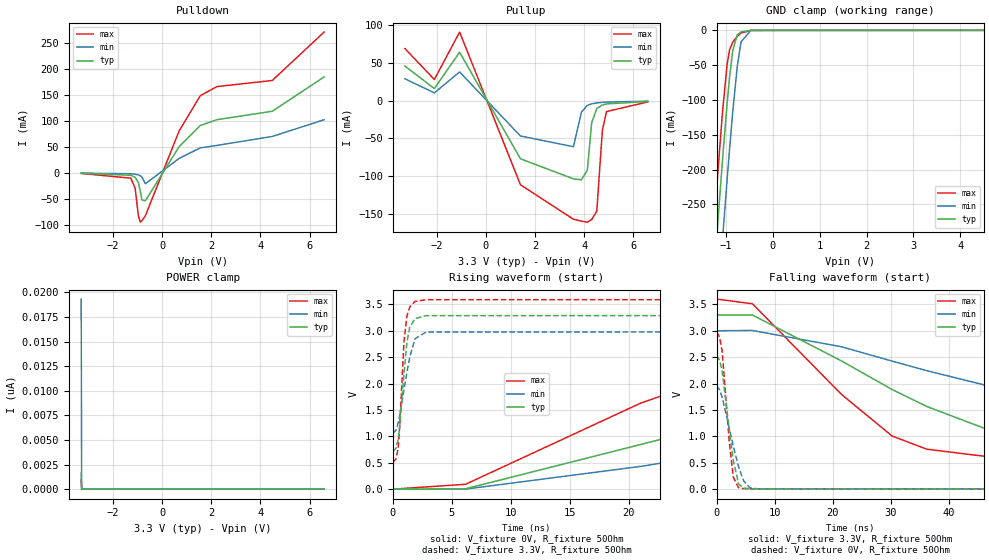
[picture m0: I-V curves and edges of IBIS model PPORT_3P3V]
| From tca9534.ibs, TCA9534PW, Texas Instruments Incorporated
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[Model]   PPORT_3P3V
Model_type   I/O
Polarity   Non-Inverting
Enable   Active-Low
Vinl = .8
Vinh = 2
Vmeas = 1.65
Vref = 3.3
Cref = 15pF
Rref = 50
|   typ   min   max
|   (nom PVT)   (slow PVT)   (fast PVT)
C_comp   2.468p   2.379p   2.720p
|C_comp (ON state)   2.695p   2.535p   2.941p
|C_comp (OFF state)   2.468p   2.379p   2.720p
| Where   nom PVT is  Nominal Process, 3.3V, 27C
|   Fast PVT is Strong Process, 3.6V, -40C
|   Slow PVT is Weak Process, 3.0V, 125C
[Voltage Range]   3.3   3   3.6
[Temperature Range]   27   125   -40
[Pullup Reference]   3.3   3   3.6
[Pulldown Reference]   -0   -0   -0
[Power Clamp Reference]   3.3   3   3.6
[GND Clamp Reference]   -0   -0   -0
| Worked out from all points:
|   slope of the pulldown table from 0 to 0.495 V, typ, clamps not added: 13.1 ohm
|   slope of the pullup table from 0 to 0.495 V, typ, clamps not added: 14.2 ohm
|   GND clamp passes 1 mA (typ) near -0.62 V on its own axis
|   falling waveform, V_fixture 3.3V, R_fixture 50Ohm: 20-80 % time 27.7ns typ, 49.7ns min, 17.6ns max; typ from 3.3 V to 0.708 V
|   rising waveform, V_fixture 0V, R_fixture 50Ohm: 20-80 % time 30.4ns typ, 44.4ns min, 19.6ns max; typ from 0 V to 2.53 V
|   rising waveform, V_fixture 3.3V, R_fixture 50Ohm: 20-80 % time 596ps typ, 918ps min, 448ps max; typ from 0.708 V to 3.3 V
|   falling waveform, V_fixture 0V, R_fixture 50Ohm: 20-80 % time 1.69ns typ, 2.5ns min, 1.29ns max; typ from 2.53 V to 0 V
[Pulldown]
|   Voltage   I(typ)   I(min)   I(max)
-3.3V     -639.1uA   -277.8uA   -1.004mA
-1.28V    -4.532mA   -1.594mA   -10.09mA
-1.102V   -8.451mA   -2.443mA   -29.46mA
-973.5mV  -18.23mA   -3.774mA   -81.98mA
-894.3mV  -35.11mA   -5.41mA    -95.02mA
-825mV    -52.14mA   -8.089mA   -92.21mA
-686.4mV  -53.71mA   -20.79mA   -82.53mA
689.7mV   50.71mA    28.1mA     81.12mA
1.551V    91.54mA    48.35mA    149.1mA
2.224V    102.7mA    53.06mA    166.5mA
4.481V    119mA      70.39mA    178.4mA
6.59V     185.1mA    102.6mA    271.7mA
[GND Clamp]
|   Voltage   I(typ)   I(min)   I(max)
-3.3V     -2.346A    -2.455A    -2.279A
-1.32V    -412.1mA   -528.2mA   -339.5mA
-1.261V   -356.7mA   -472.8mA   -284.2mA
-1.211V   -311mA     -426.9mA   -238.7mA
-1.073V   -186.8mA   -300.8mA   -117.9mA
-973.5mV  -104.8mA   -214mA     -48.36mA
-924mV    -68.57mA   -172.4mA   -28.41mA
-854.7mV  -29.13mA   -117.3mA   -17.02mA
-755.7mV  -6.263mA   -50.5mA    -8.57mA
-676.5mV  -2.232mA   -16.53mA   -3.84mA
-468.6mV  -59.06uA   -162.9uA   -73.71uA
6.59V     0A         0A         0A
[Pullup]
|   Voltage   I(typ)   I(min)   I(max)
-3.3V     45.75mA    28.86mA    68.89mA
-2.102V   15.93mA    10.19mA    27.88mA
-1.073V   64.02mA    37.93mA    90.75mA
1.403V    -77.2mA    -46.97mA   -111.6mA
3.561V    -103.7mA   -61.12mA   -157.3mA
3.887V    -105mA     -15.25mA   -159.8mA
4.125V    -92.21mA   -6.397mA   -161.2mA
4.303V    -29.45mA   -4.336mA   -157.7mA
4.511V    -10.5mA    -3.127mA   -146.5mA
4.739V    -5.875mA   -2.386mA   -39.33mA
4.907V    -4.4mA     -2.028mA   -14.57mA
6.59V     -1.226mA   -802.4uA   -1.786mA
[POWER Clamp]
|   Voltage   I(typ)   I(min)   I(max)
-3.3V     1.647nA    19.33nA    956.4pA
-3.28V    0A         0A         0A
-3.27V    0A         0A         0A
6.59V     0A         0A         0A
[Ramp]
R_load = 50
|   typ   min   max
dV/dt_r   1.51993/3.02056e-08   1.17587/4.4155e-08   1.78552/1.95401e-08
dV/dt_f   1.55534/2.77013e-08   1.1674/4.95217e-08   1.85505/1.75559e-08
[Falling Waveform]
V_fixture = 3.3V
V_fixture_min = 3V
V_fixture_max = 3.6V
R_fixture = 50Ohm
C_fixture = 0F
|   Time   V(typ)   V(min)   V(max)
0s        3.3V       3V         3.6V
6.173ns   3.298V     3.005V     3.511V
21.49ns   2.429V     2.697V     1.795V
30.21ns   1.887V     2.425V     1.006V
36.2ns    1.565V     2.243V     756.4mV
46.26ns   1.145V     1.969V     620.5mV
58.44ns   913.1mV    1.696V     565.3mV
80.73ns   785.3mV    1.362V     531.6mV
119ns     727mV      1.15V      512.5mV
399.9ns   707.8mV    1.054V     508.3mV
[Rising Waveform]
V_fixture = 0V
V_fixture_min = 0V
V_fixture_max = 0V
R_fixture = 50Ohm
C_fixture = 0F
|   Time   V(typ)   V(min)   V(max)
0s        1.304uV    1.505uV    1.202uV
6.173ns   6.889mV    1.278mV    92.64mV
21.01ns   845.3mV    430.8mV    1.628V
30.85ns   1.407V     777.4mV    2.394V
39.01ns   1.781V     1.033V     2.707V
49.88ns   2.131V     1.306V     2.849V
61.37ns   2.318V     1.522V     2.908V
80.73ns   2.441V     1.749V     2.947V
119ns     2.51V      1.9V       2.969V
399.9ns   2.533V     1.96V      2.976V
[Rising Waveform]
V_fixture = 3.3V
V_fixture_min = 3V
V_fixture_max = 3.6V
R_fixture = 50Ohm
C_fixture = 0F
|   Time   V(typ)   V(min)   V(max)
0s        707.8mV    1.054V     508.3mV
269.2ps   776.3mV    1.116V     573.1mV
450ps     939.5mV    1.247V     769.1mV
584.7ps   1.178V     1.388V     1.186V
956.1ps   2.201V     1.883V     2.81V
1.197ns   2.773V     2.208V     3.274V
1.441ns   3.07V      2.502V     3.451V
1.887ns   3.23V      2.85V      3.555V
2.833ns   3.286V     2.976V     3.588V
399.9ns   3.3V       3V         3.6V
[Falling Waveform]
|Gnd
V_fixture = 0V
V_fixture_min = 0V
V_fixture_max = 0V
R_fixture = 50Ohm
C_fixture = 0F
|   Time   V(typ)   V(min)   V(max)
0s        2.533V     1.96V      2.976V
517.4ps   2.442V     1.886V     2.882V
956.1ps   2.249V     1.747V     2.628V
2.221ns   1.103V     1.146V     860.3mV
2.896ns   543.8mV    809.6mV    225.7mV
3.792ns   99mV       421.9mV    26.5mV
4.663ns   19.84mV    158.6mV    9.685mV
5.747ns   7.222mV    22.87mV    7.517mV
7.204ns   6.03mV     6.067mV    6.901mV
399.9ns   1.304uV    1.505uV    1.202uV
